VERSION 5.7 ;
  NOWIREEXTENSIONATPIN ON ;
  DIVIDERCHAR "/" ;
  BUSBITCHARS "[]" ;
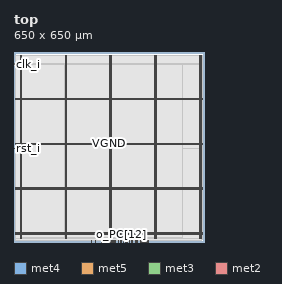
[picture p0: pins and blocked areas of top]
MACRO top
  CLASS BLOCK ;
  FOREIGN top ;
  ORIGIN 0.000 0.000 ;
  SIZE 650.000 BY 650.000 ;
  PIN VGND
    DIRECTION INOUT ;
    USE GROUND ;
    PORT
      LAYER met4 ;
        RECT 24.340 10.640 25.940 636.720 ;
    END
    PORT
      LAYER met4 ;
        RECT 177.940 10.640 179.540 636.720 ;
    END
    PORT
      LAYER met4 ;
        RECT 331.540 10.640 333.140 636.720 ;
    END
    PORT
      LAYER met4 ;
        RECT 485.140 10.640 486.740 636.720 ;
    END
    PORT
      LAYER met4 ;
        RECT 638.740 10.640 640.340 636.720 ;
    END
    PORT
      LAYER met5 ;
        RECT 5.280 30.030 644.700 31.630 ;
    END
    PORT
      LAYER met5 ;
        RECT 5.280 183.210 644.700 184.810 ;
    END
    PORT
      LAYER met5 ;
        RECT 5.280 336.390 644.700 337.990 ;
    END
    PORT
      LAYER met5 ;
        RECT 5.280 489.570 644.700 491.170 ;
    END
  END VGND
  PIN VPWR
    DIRECTION INOUT ;
    USE POWER ;
    PORT
      LAYER met4 ;
        RECT 21.040 10.640 22.640 636.720 ;
    END
    PORT
      LAYER met4 ;
        RECT 174.640 10.640 176.240 636.720 ;
    END
    PORT
      LAYER met4 ;
        RECT 328.240 10.640 329.840 636.720 ;
    END
    PORT
      LAYER met4 ;
        RECT 481.840 10.640 483.440 636.720 ;
    END
    PORT
      LAYER met4 ;
        RECT 635.440 10.640 637.040 636.720 ;
    END
    PORT
      LAYER met5 ;
        RECT 5.280 26.730 644.700 28.330 ;
    END
    PORT
      LAYER met5 ;
        RECT 5.280 179.910 644.700 181.510 ;
    END
    PORT
      LAYER met5 ;
        RECT 5.280 333.090 644.700 334.690 ;
    END
    PORT
      LAYER met5 ;
        RECT 5.280 486.270 644.700 487.870 ;
    END
  END VPWR
  PIN clk_i
    DIRECTION INPUT ;
    USE SIGNAL ;
    ANTENNAGATEAREA 0.852000 ;
    ANTENNADIFFAREA 0.434700 ;
    PORT
      LAYER met3 ;
        RECT 0.000 608.640 4.000 609.240 ;
    END
  END clk_i
  PIN o_PC[0]
    DIRECTION OUTPUT ;
    USE SIGNAL ;
    ANTENNADIFFAREA 0.445500 ;
    PORT
      LAYER met2 ;
        RECT 328.530 0.000 328.810 4.000 ;
    END
  END o_PC[0]
  PIN o_PC[10]
    DIRECTION OUTPUT ;
    USE SIGNAL ;
    ANTENNADIFFAREA 0.445500 ;
    PORT
      LAYER met2 ;
        RECT 357.510 0.000 357.790 4.000 ;
    END
  END o_PC[10]
  PIN o_PC[11]
    DIRECTION OUTPUT ;
    USE SIGNAL ;
    ANTENNADIFFAREA 0.445500 ;
    PORT
      LAYER met2 ;
        RECT 363.950 0.000 364.230 4.000 ;
    END
  END o_PC[11]
  PIN o_PC[12]
    DIRECTION OUTPUT ;
    USE SIGNAL ;
    ANTENNADIFFAREA 0.445500 ;
    PORT
      LAYER met2 ;
        RECT 367.170 0.000 367.450 4.000 ;
    END
  END o_PC[12]
  PIN o_PC[13]
    DIRECTION OUTPUT ;
    USE SIGNAL ;
    ANTENNADIFFAREA 0.445500 ;
    PORT
      LAYER met2 ;
        RECT 373.610 0.000 373.890 4.000 ;
    END
  END o_PC[13]
  PIN o_PC[14]
    DIRECTION OUTPUT ;
    USE SIGNAL ;
    ANTENNADIFFAREA 0.445500 ;
    PORT
      LAYER met2 ;
        RECT 380.050 0.000 380.330 4.000 ;
    END
  END o_PC[14]
  PIN o_PC[15]
    DIRECTION OUTPUT ;
    USE SIGNAL ;
    ANTENNADIFFAREA 0.445500 ;
    PORT
      LAYER met2 ;
        RECT 386.490 0.000 386.770 4.000 ;
    END
  END o_PC[15]
  PIN o_PC[16]
    DIRECTION OUTPUT ;
    USE SIGNAL ;
    ANTENNADIFFAREA 0.445500 ;
    PORT
      LAYER met2 ;
        RECT 389.710 0.000 389.990 4.000 ;
    END
  END o_PC[16]
  PIN o_PC[17]
    DIRECTION OUTPUT ;
    USE SIGNAL ;
    ANTENNADIFFAREA 0.445500 ;
    PORT
      LAYER met2 ;
        RECT 396.150 0.000 396.430 4.000 ;
    END
  END o_PC[17]
  PIN o_PC[18]
    DIRECTION OUTPUT ;
    USE SIGNAL ;
    ANTENNADIFFAREA 0.445500 ;
    PORT
      LAYER met2 ;
        RECT 405.810 0.000 406.090 4.000 ;
    END
  END o_PC[18]
  PIN o_PC[19]
    DIRECTION OUTPUT ;
    USE SIGNAL ;
    ANTENNADIFFAREA 0.445500 ;
    PORT
      LAYER met2 ;
        RECT 415.470 0.000 415.750 4.000 ;
    END
  END o_PC[19]
  PIN o_PC[1]
    DIRECTION OUTPUT ;
    USE SIGNAL ;
    ANTENNADIFFAREA 0.445500 ;
    PORT
      LAYER met2 ;
        RECT 325.310 0.000 325.590 4.000 ;
    END
  END o_PC[1]
  PIN o_PC[20]
    DIRECTION OUTPUT ;
    USE SIGNAL ;
    ANTENNADIFFAREA 0.445500 ;
    PORT
      LAYER met2 ;
        RECT 418.690 0.000 418.970 4.000 ;
    END
  END o_PC[20]
  PIN o_PC[21]
    DIRECTION OUTPUT ;
    USE SIGNAL ;
    ANTENNADIFFAREA 0.445500 ;
    PORT
      LAYER met2 ;
        RECT 421.910 0.000 422.190 4.000 ;
    END
  END o_PC[21]
  PIN o_PC[22]
    DIRECTION OUTPUT ;
    USE SIGNAL ;
    ANTENNADIFFAREA 0.445500 ;
    PORT
      LAYER met2 ;
        RECT 402.590 0.000 402.870 4.000 ;
    END
  END o_PC[22]
  PIN o_PC[23]
    DIRECTION OUTPUT ;
    USE SIGNAL ;
    ANTENNADIFFAREA 0.445500 ;
    PORT
      LAYER met2 ;
        RECT 431.570 0.000 431.850 4.000 ;
    END
  END o_PC[23]
  PIN o_PC[24]
    DIRECTION OUTPUT ;
    USE SIGNAL ;
    ANTENNADIFFAREA 0.445500 ;
    PORT
      LAYER met2 ;
        RECT 441.230 0.000 441.510 4.000 ;
    END
  END o_PC[24]
  PIN o_PC[25]
    DIRECTION OUTPUT ;
    USE SIGNAL ;
    ANTENNADIFFAREA 0.445500 ;
    PORT
      LAYER met2 ;
        RECT 444.450 0.000 444.730 4.000 ;
    END
  END o_PC[25]
  PIN o_PC[26]
    DIRECTION OUTPUT ;
    USE SIGNAL ;
    ANTENNADIFFAREA 0.445500 ;
    PORT
      LAYER met2 ;
        RECT 447.670 0.000 447.950 4.000 ;
    END
  END o_PC[26]
  PIN o_PC[27]
    DIRECTION OUTPUT ;
    USE SIGNAL ;
    ANTENNADIFFAREA 0.445500 ;
    PORT
      LAYER met2 ;
        RECT 460.550 0.000 460.830 4.000 ;
    END
  END o_PC[27]
  PIN o_PC[28]
    DIRECTION OUTPUT ;
    USE SIGNAL ;
    ANTENNADIFFAREA 0.445500 ;
    PORT
      LAYER met2 ;
        RECT 434.790 0.000 435.070 4.000 ;
    END
  END o_PC[28]
  PIN o_PC[29]
    DIRECTION OUTPUT ;
    USE SIGNAL ;
    ANTENNADIFFAREA 0.445500 ;
    PORT
      LAYER met2 ;
        RECT 454.110 0.000 454.390 4.000 ;
    END
  END o_PC[29]
  PIN o_PC[2]
    DIRECTION OUTPUT ;
    USE SIGNAL ;
    ANTENNADIFFAREA 0.445500 ;
    PORT
      LAYER met2 ;
        RECT 338.190 0.000 338.470 4.000 ;
    END
  END o_PC[2]
  PIN o_PC[30]
    DIRECTION OUTPUT ;
    USE SIGNAL ;
    ANTENNADIFFAREA 0.445500 ;
    PORT
      LAYER met2 ;
        RECT 450.890 0.000 451.170 4.000 ;
    END
  END o_PC[30]
  PIN o_PC[31]
    DIRECTION OUTPUT ;
    USE SIGNAL ;
    ANTENNADIFFAREA 0.445500 ;
    PORT
      LAYER met2 ;
        RECT 457.330 0.000 457.610 4.000 ;
    END
  END o_PC[31]
  PIN o_PC[3]
    DIRECTION OUTPUT ;
    USE SIGNAL ;
    ANTENNADIFFAREA 0.445500 ;
    PORT
      LAYER met2 ;
        RECT 341.410 0.000 341.690 4.000 ;
    END
  END o_PC[3]
  PIN o_PC[4]
    DIRECTION OUTPUT ;
    USE SIGNAL ;
    ANTENNADIFFAREA 0.445500 ;
    PORT
      LAYER met2 ;
        RECT 322.090 0.000 322.370 4.000 ;
    END
  END o_PC[4]
  PIN o_PC[5]
    DIRECTION OUTPUT ;
    USE SIGNAL ;
    ANTENNADIFFAREA 0.445500 ;
    PORT
      LAYER met2 ;
        RECT 318.870 0.000 319.150 4.000 ;
    END
  END o_PC[5]
  PIN o_PC[6]
    DIRECTION OUTPUT ;
    USE SIGNAL ;
    ANTENNADIFFAREA 0.445500 ;
    PORT
      LAYER met2 ;
        RECT 331.750 0.000 332.030 4.000 ;
    END
  END o_PC[6]
  PIN o_PC[7]
    DIRECTION OUTPUT ;
    USE SIGNAL ;
    ANTENNADIFFAREA 0.445500 ;
    PORT
      LAYER met2 ;
        RECT 334.970 0.000 335.250 4.000 ;
    END
  END o_PC[7]
  PIN o_PC[8]
    DIRECTION OUTPUT ;
    USE SIGNAL ;
    ANTENNADIFFAREA 0.445500 ;
    PORT
      LAYER met2 ;
        RECT 344.630 0.000 344.910 4.000 ;
    END
  END o_PC[8]
  PIN o_PC[9]
    DIRECTION OUTPUT ;
    USE SIGNAL ;
    ANTENNADIFFAREA 0.445500 ;
    PORT
      LAYER met2 ;
        RECT 347.850 0.000 348.130 4.000 ;
    END
  END o_PC[9]
  PIN o_RD_We
    DIRECTION OUTPUT ;
    USE SIGNAL ;
    ANTENNADIFFAREA 0.445500 ;
    PORT
      LAYER met2 ;
        RECT 264.130 0.000 264.410 4.000 ;
    END
  END o_RD_We
  PIN o_State[0]
    DIRECTION OUTPUT ;
    USE SIGNAL ;
    ANTENNADIFFAREA 0.445500 ;
    PORT
      LAYER met2 ;
        RECT 280.230 0.000 280.510 4.000 ;
    END
  END o_State[0]
  PIN o_State[1]
    DIRECTION OUTPUT ;
    USE SIGNAL ;
    ANTENNADIFFAREA 0.445500 ;
    PORT
      LAYER met2 ;
        RECT 299.550 0.000 299.830 4.000 ;
    END
  END o_State[1]
  PIN rst_i
    DIRECTION INPUT ;
    USE SIGNAL ;
    ANTENNAGATEAREA 0.159000 ;
    PORT
      LAYER met3 ;
        RECT 0.000 319.640 4.000 320.240 ;
    END
  END rst_i
  OBS
      LAYER nwell ;
        RECT 5.330 10.795 644.650 636.565 ;
      LAYER li1 ;
        RECT 5.520 10.795 644.460 636.565 ;
      LAYER met1 ;
        RECT 4.210 9.900 644.460 636.720 ;
      LAYER met2 ;
        RECT 4.230 4.280 642.980 636.665 ;
        RECT 4.230 3.670 263.850 4.280 ;
        RECT 264.690 3.670 279.950 4.280 ;
        RECT 280.790 3.670 299.270 4.280 ;
        RECT 300.110 3.670 318.590 4.280 ;
        RECT 319.430 3.670 321.810 4.280 ;
        RECT 322.650 3.670 325.030 4.280 ;
        RECT 325.870 3.670 328.250 4.280 ;
        RECT 329.090 3.670 331.470 4.280 ;
        RECT 332.310 3.670 334.690 4.280 ;
        RECT 335.530 3.670 337.910 4.280 ;
        RECT 338.750 3.670 341.130 4.280 ;
        RECT 341.970 3.670 344.350 4.280 ;
        RECT 345.190 3.670 347.570 4.280 ;
        RECT 348.410 3.670 357.230 4.280 ;
        RECT 358.070 3.670 363.670 4.280 ;
        RECT 364.510 3.670 366.890 4.280 ;
        RECT 367.730 3.670 373.330 4.280 ;
        RECT 374.170 3.670 379.770 4.280 ;
        RECT 380.610 3.670 386.210 4.280 ;
        RECT 387.050 3.670 389.430 4.280 ;
        RECT 390.270 3.670 395.870 4.280 ;
        RECT 396.710 3.670 402.310 4.280 ;
        RECT 403.150 3.670 405.530 4.280 ;
        RECT 406.370 3.670 415.190 4.280 ;
        RECT 416.030 3.670 418.410 4.280 ;
        RECT 419.250 3.670 421.630 4.280 ;
        RECT 422.470 3.670 431.290 4.280 ;
        RECT 432.130 3.670 434.510 4.280 ;
        RECT 435.350 3.670 440.950 4.280 ;
        RECT 441.790 3.670 444.170 4.280 ;
        RECT 445.010 3.670 447.390 4.280 ;
        RECT 448.230 3.670 450.610 4.280 ;
        RECT 451.450 3.670 453.830 4.280 ;
        RECT 454.670 3.670 457.050 4.280 ;
        RECT 457.890 3.670 460.270 4.280 ;
        RECT 461.110 3.670 642.980 4.280 ;
      LAYER met3 ;
        RECT 3.990 609.640 640.330 636.645 ;
        RECT 4.400 608.240 640.330 609.640 ;
        RECT 3.990 320.640 640.330 608.240 ;
        RECT 4.400 319.240 640.330 320.640 ;
        RECT 3.990 10.715 640.330 319.240 ;
      LAYER met4 ;
        RECT 23.295 14.455 23.940 608.425 ;
        RECT 26.340 14.455 174.240 608.425 ;
        RECT 176.640 14.455 177.540 608.425 ;
        RECT 179.940 14.455 327.840 608.425 ;
        RECT 330.240 14.455 331.140 608.425 ;
        RECT 333.540 14.455 481.440 608.425 ;
        RECT 483.840 14.455 484.740 608.425 ;
        RECT 487.140 14.455 575.625 608.425 ;
  END
END top
END LIBRARY

